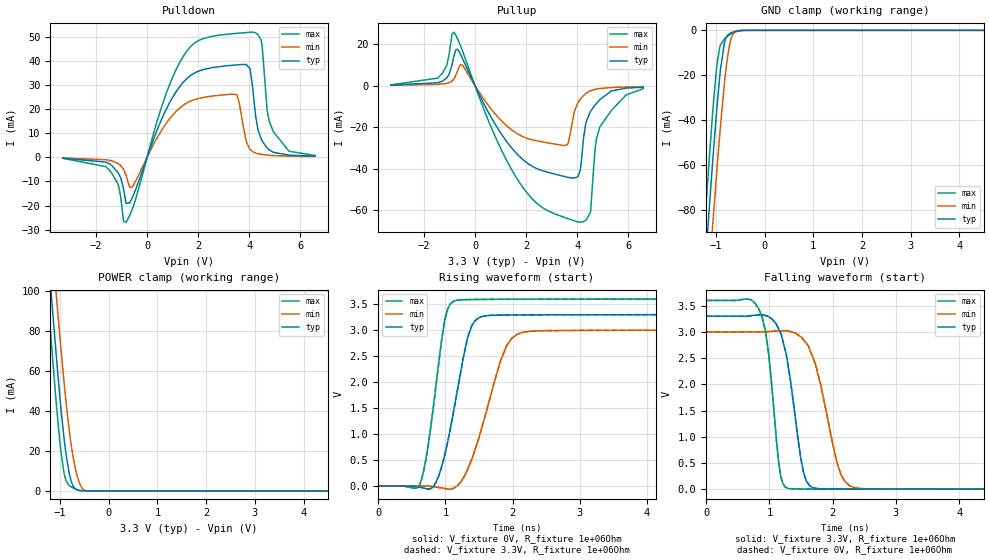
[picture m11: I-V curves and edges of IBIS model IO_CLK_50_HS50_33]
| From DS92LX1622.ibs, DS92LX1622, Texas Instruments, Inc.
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|   IO_CLK_50_HS50 3.3V CLK model
[Model]   IO_CLK_50_HS50_33
Model_type   I/O
Polarity   Non-Inverting
Enable   Active-Low
Vinl = 0.8
Vinh = 2
Vmeas = 1.65
Vref = 3.3
Cref = 1pF
Rref = 1000000
|   typ   min   max
|   (nom)   (fast)   (slow)
C_comp   0.766pF   0.766pF   1.11pF
[Voltage Range]   3.3   3   3.6
[Temperature Range]   25   105   -40
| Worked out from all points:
|   slope of the pulldown table from 0 to 0.495 V, typ, clamps not added: 35.6 ohm
|   slope of the pullup table from 0 to 0.495 V, typ, clamps not added: 40.7 ohm
|   GND clamp passes 1 mA (typ) near -0.67 V on its own axis
|   POWER clamp passes 1 mA (typ) near -0.68 V on its own axis
|   falling waveform, V_fixture 3.3V, R_fixture 1e+06Ohm: 20-80 % time 235ps typ, 327ps min, 176ps max; typ from 3.3 V to 0 V
|   rising waveform, V_fixture 0V, R_fixture 1e+06Ohm: 20-80 % time 294ps typ, 401ps min, 216ps max; typ from 0 V to 3.3 V
|   rising waveform, V_fixture 3.3V, R_fixture 1e+06Ohm: 20-80 % time 294ps typ, 401ps min, 216ps max; typ from 0 V to 3.3 V
|   falling waveform, V_fixture 0V, R_fixture 1e+06Ohm: 20-80 % time 235ps typ, 327ps min, 176ps max; typ from 3.3 V to 0 V
[Pulldown]
|   Voltage   I(typ)   I(min)   I(max)
-3.3V     -398.4uA   -308.3uA   -441uA
-1.607V   -2.004mA   -1.037mA   -3.904mA
-1.142V   -6.345mA   -2.536mA   -11.05mA
-825mV    -19.03mA   -7.469mA   -26.88mA
-597.3mV  -17.1mA    -12.5mA    -21.91mA
1.472V    31.7mA     21.95mA    42.69mA
3.472V    38.2mA     26.05mA    51.26mA
4.125V    29.83mA    2.412mA    51.83mA
4.471V    7.548mA    1.199mA    48.51mA
4.699V    3.892mA    904.3uA    19.71mA
4.947V    2.046mA    714.9uA    10.67mA
6.59V     463.1uA    300.8uA    707.4uA
[GND Clamp]
|   Voltage   I(typ)   I(min)   I(max)
-3.3V     -796.6mA   -801.1mA   -797.6mA
-1.231V   -109mA     -136.6mA   -87.53mA
-1.201V   -99.76mA   -127.6mA   -78.02mA
-1.122V   -75.44mA   -103.8mA   -53.38mA
-1.073V   -60.7mA    -89.17mA   -38.86mA
-983.4mV  -35.83mA   -63.72mA   -16.72mA
-904.2mV  -17.3mA    -42.57mA   -6.459mA
-815.1mV  -4.796mA   -21.95mA   -3.664mA
-735.9mV  -1.721mA   -8.675mA   -2.309mA
-676.5mV  -1.02mA    -3.094mA   -1.5mA
-409.2mV  -14.47uA   -12.9uA    -29.14uA
6.59V     0A         0A         0A
[Pullup]
|   Voltage   I(typ)   I(min)   I(max)
-3.3V     325uA      225.8uA    411.8uA
-1.468V   1.438mA    671.4uA    3.669mA
-825mV    14.44mA    3.308mA    25.83mA
-508.2mV  13.56mA    10.06mA    17.31mA
1.739V    -34mA      -23.65mA   -46.49mA
3.61V     -43.98mA   -28.38mA   -63.84mA
4.125V    -40.45mA   -6.45mA    -65.67mA
4.333V    -18.6mA    -3.802mA   -64.75mA
4.521V    -12.44mA   -2.444mA   -60.89mA
4.709V    -9.242mA   -1.732mA   -29.88mA
4.897V    -6.655mA   -1.329mA   -19.7mA
6.59V     -713uA     -421.4uA   -1.393mA
[POWER Clamp]
|   Voltage   I(typ)   I(min)   I(max)
-3.3V     802.5mA    808.9mA    802mA
-1.31V    139.8mA    168.7mA    117.3mA
-1.231V   114.8mA    144.4mA    91.52mA
-1.211V   108.6mA    138.4mA    85.16mA
-1.132V   84.2mA     114.6mA    60.34mA
-1.082V   69.45mA    100mA      45.61mA
-924mV    27.79mA    56.17mA    9.883mA
-795.3mV  7.174mA    27.45mA    2.45mA
-656.7mV  613.2uA    8.486mA    694.4uA
-547.8mV  99.32uA    1.452mA    115.9uA
-409.2mV  3.688uA    30.95uA    3.022uA
6.59V     0A         0A         0A
[Ramp]
R_load = 1e+06
|   typ   min   max
dV/dt_r   1.97993/2.93867e-10   1.7999/4.01273e-10   2.15993/2.1602e-10
dV/dt_f   1.97994/2.34991e-10   1.79991/3.26556e-10   2.15994/1.75814e-10
[Falling Waveform]
V_fixture = 3.3V
V_fixture_min = 3V
V_fixture_max = 3.6V
R_fixture = 1e+06Ohm
C_fixture = 0F
|   Time   V(typ)   V(min)   V(max)
0s        3.3V       3V         3.6V
880.1ps   3.324V     3.001V     3.305V
989.6ps   3.289V     3.008V     2.567V
1.149ns   3.052V     3.021V     486.8mV
1.289ns   2.404V     3.018V     17.7mV
1.583ns   159.4mV    2.783V     2.849mV
1.728ns   16.75mV    2.389V     2.07mV
2.13ns    2.744mV    283.3mV    1.188mV
2.345ns   1.824mV    28.61mV    995.3uV
10.05ns   105.1uV    134.9uV    93.78uV
[Rising Waveform]
V_fixture = 0V
V_fixture_min = 0V
V_fixture_max = 0V
R_fixture = 1e+06Ohm
C_fixture = 0F
|   Time   V(typ)   V(min)   V(max)
0s        187.7nV    2.409uV    5.075uV
621ps     -25.15mV   268.7uV    38.18mV
828.7ps   3.004mV    -16.09mV   1.599V
989.6ps   594.6mV    -49.13mV   3.191V
1.149ns   1.629V     -23.79mV   3.57V
1.329ns   2.845V     309mV      3.589V
1.436ns   3.173V     675.1mV    3.592V
1.816ns   3.291V     2.39V      3.595V
2.13ns    3.294V     2.951V     3.597V
10.05ns   3.3V       3V         3.6V
[Rising Waveform]
V_fixture = 3.3V
V_fixture_min = 3V
V_fixture_max = 3.6V
R_fixture = 1e+06Ohm
C_fixture = 0F
|   Time   V(typ)   V(min)   V(max)
0s        105.6uV    135.7uV    92.26uV
621ps     -25.03mV   402.1uV    38.52mV
828.7ps   3.49mV     -15.95mV   1.6V
989.6ps   595.5mV    -48.87mV   3.192V
1.149ns   1.63V      -23.19mV   3.57V
1.329ns   2.846V     310mV      3.589V
1.436ns   3.174V     676.3mV    3.592V
1.816ns   3.291V     2.391V     3.595V
2.13ns    3.294V     2.951V     3.597V
10.05ns   3.3V       3V         3.6V
[Falling Waveform]
|Gnd
V_fixture = 0V
V_fixture_min = 0V
V_fixture_max = 0V
R_fixture = 1e+06Ohm
C_fixture = 0F
|   Time   V(typ)   V(min)   V(max)
0s        3.3V       3V         3.6V
880.1ps   3.324V     3V         3.305V
989.6ps   3.289V     3.008V     2.567V
1.149ns   3.052V     3.02V      486.3mV
1.289ns   2.404V     3.018V     17.56mV
1.583ns   159mV      2.783V     2.743mV
1.728ns   16.57mV    2.388V     1.969mV
2.13ns    2.609mV    282.7mV    1.095mV
2.345ns   1.698mV    28.33mV    903.1uV
10.05ns   -346.5nV   1.621uV    6.598uV
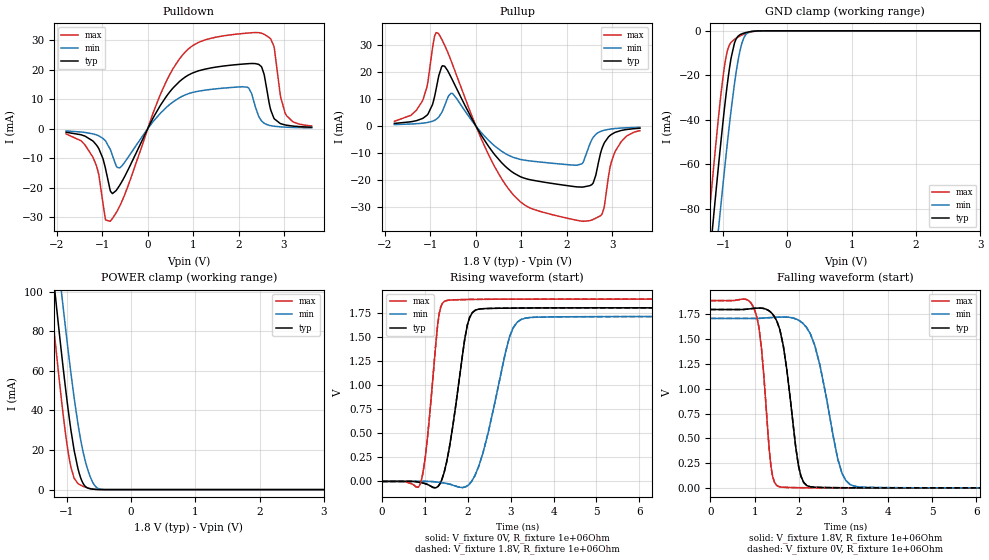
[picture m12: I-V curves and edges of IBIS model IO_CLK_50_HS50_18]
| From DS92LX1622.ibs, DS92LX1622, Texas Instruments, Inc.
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|   IO_CLK_50_HS50 1.8V CLK model
[Model]   IO_CLK_50_HS50_18
Model_type   I/O
Polarity   Non-Inverting
Enable   Active-Low
Vinl = 0.63
Vinh = 1.17
Vmeas = 0.9
Vref = 1.8
Cref = 1pF
Rref = 1000000
|   typ   min   max
|   (nom)   (fast)   (slow)
C_comp   1.11pF   1.11pF   1.11pF
[Voltage Range]   1.8   1.71   1.89
[Temperature Range]   25   105   -40
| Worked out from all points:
|   slope of the pulldown table from 0 to 0.27 V, typ, clamps not added: 35.1 ohm
|   slope of the pullup table from 0 to 0.27 V, typ, clamps not added: 37 ohm
|   GND clamp passes 1 mA (typ) near -0.67 V on its own axis
|   POWER clamp passes 1 mA (typ) near -0.68 V on its own axis
|   falling waveform, V_fixture 1.8V, R_fixture 1e+06Ohm: 20-80 % time 300ps typ, 455ps min, 205ps max; typ from 1.8 V to 0 V
|   rising waveform, V_fixture 0V, R_fixture 1e+06Ohm: 20-80 % time 343ps typ, 516ps min, 231ps max; typ from 0 V to 1.8 V
|   rising waveform, V_fixture 1.8V, R_fixture 1e+06Ohm: 20-80 % time 343ps typ, 516ps min, 231ps max; typ from 0 V to 1.8 V
|   falling waveform, V_fixture 0V, R_fixture 1e+06Ohm: 20-80 % time 300ps typ, 455ps min, 205ps max; typ from 1.8 V to 0 V
[Pulldown]
|   Voltage   I(typ)   I(min)   I(max)
-1.795V   -1.157mA   -724.4uA   -1.742mA
-1.211V   -4.061mA   -1.684mA   -9.46mA
-924mV    -13.77mA   -4.162mA   -30.91mA
-825mV    -20.83mA   -6.906mA   -31.33mA
-607.2mV  -18.91mA   -13.13mA   -25.92mA
699.6mV   16.03mA    10.54mA    23.7mA
2.195V    22.06mA    14.1mA     32.44mA
2.363V    22.11mA    7.84mA     32.62mA
2.511V    20.86mA    2.611mA    32.37mA
2.788V    3.369mA    866.9uA    27.24mA
3.026V    1.312mA    577.4uA    5.296mA
3.61V     564uA      335.2uA    995.5uA
[GND Clamp]
|   Voltage   I(typ)   I(min)   I(max)
-1.795V   -292.4mA   -313.9mA   -276.9mA
-1.31V    -134.1mA   -161mA     -113.3mA
-1.201V   -99.76mA   -127.6mA   -78.02mA
-1.171V   -90.55mA   -118.6mA   -68.64mA
-1.142V   -81.44mA   -109.7mA   -59.42mA
-1.063V   -57.82mA   -86.28mA   -36.08mA
-953.7mV  -28.32mA   -55.58mA   -11.54mA
-874.5mV  -11.92mA   -35.21mA   -5.103mA
-805.2mV  -4.099mA   -19.97mA   -3.476mA
-696.3mV  -1.21mA    -4.515mA   -1.749mA
-468.6mV  -56.35uA   -42.02uA   -115.6uA
6.59V     0A         0A         0A
[Pullup]
|   Voltage   I(typ)   I(min)   I(max)
-1.795V   961.9uA    530.7uA    1.732mA
-1.181V   2.739mA    1.035mA    9.145mA
-914.1mV  10.54mA    2.066mA    32.84mA
-825mV    17.95mA    3.193mA    34.2mA
-518.1mV  17.06mA    12.01mA    22.9mA
699.6mV   -15.69mA   -10.65mA   -22.82mA
2.363V    -22.53mA   -13.37mA   -35.21mA
2.581V    -21.1mA    -4.195mA   -34.52mA
2.779V    -8.126mA   -1.78mA    -32.45mA
2.917V    -4.04mA    -1.236mA   -18.71mA
3.194V    -1.656mA   -759.2uA   -5.867mA
3.61V     -845.5uA   -486.4uA   -1.761mA
[POWER Clamp]
|   Voltage   I(typ)   I(min)   I(max)
-1.795V   298.2mA    321.6mA    281.1mA
-1.261V   124.1mA    153.5mA    101.1mA
-1.221V   111.7mA    141.4mA    88.33mA
-1.181V   99.34mA    129.4mA    75.72mA
-1.073V   66.56mA    97.12mA    42.78mA
-973.5mV  39.44mA    69.22mA    18.22mA
-884.4mV  19.85mA    46.39mA    5.732mA
-775.5mV  5.325mA    23.95mA    2.121mA
-656.7mV  613.2uA    8.486mA    694.4uA
-547.8mV  99.32uA    1.452mA    115.9uA
-409.2mV  3.688uA    30.94uA    3.021uA
6.59V     0A         0A         0A
[Ramp]
R_load = 1e+06
|   typ   min   max
dV/dt_r   1.07996/3.43402e-10   1.02595/5.15866e-10   1.13397/2.31406e-10
dV/dt_f   1.07996/2.99937e-10   1.02595/4.5521e-10   1.13397/2.04775e-10
[Falling Waveform]
V_fixture = 1.8V
V_fixture_min = 1.71V
V_fixture_max = 1.89V
R_fixture = 1e+06Ohm
C_fixture = 0F
|   Time   V(typ)   V(min)   V(max)
0s        1.8V       1.71V      1.89V
1.009ns   1.812V     1.71V      1.784V
1.154ns   1.813V     1.712V     1.411V
1.369ns   1.77V      1.719V     213.4mV
1.538ns   1.636V     1.722V     14.21mV
1.989ns   220.8mV    1.692V     1.825mV
2.177ns   22.92mV    1.613V     1.185mV
2.874ns   1.727mV    290.7mV    429.7uV
3.149ns   1.144mV    34.81mV    326.8uV
10.05ns   56.86uV    85.65uV    41.69uV
[Rising Waveform]
V_fixture = 0V
V_fixture_min = 0V
V_fixture_max = 0V
R_fixture = 1e+06Ohm
C_fixture = 0F
|   Time   V(typ)   V(min)   V(max)
0s        779.8nV    5.958uV    1.186uV
904.8ps   -12.05mV   381.4uV    -6.906mV
1.052ns   -30.44mV   128uV      421.2mV
1.329ns   -37.28mV   -9.456mV   1.733V
1.493ns   176.3mV    -20.51mV   1.874V
1.989ns   1.622V     -44.92mV   1.886V
2.177ns   1.776V     72.8mV     1.887V
2.969ns   1.797V     1.495V     1.889V
3.248ns   1.798V     1.68V      1.89V
10.05ns   1.8V       1.71V      1.89V
[Rising Waveform]
V_fixture = 1.8V
V_fixture_min = 1.71V
V_fixture_max = 1.89V
R_fixture = 1e+06Ohm
C_fixture = 0F
|   Time   V(typ)   V(min)   V(max)
0s        56.85uV    86.11uV    41.52uV
904.8ps   -11.99mV   461uV      -6.601mV
1.052ns   -30.34mV   207.6uV    421.7mV
1.329ns   -36.84mV   -9.365mV   1.733V
1.493ns   176.9mV    -20.39mV   1.874V
1.989ns   1.623V     -44.31mV   1.886V
2.177ns   1.776V     73.6mV     1.887V
2.969ns   1.797V     1.495V     1.89V
3.248ns   1.798V     1.68V      1.89V
10.05ns   1.8V       1.71V      1.89V
[Falling Waveform]
|Gnd
V_fixture = 0V
V_fixture_min = 0V
V_fixture_max = 0V
R_fixture = 1e+06Ohm
C_fixture = 0F
|   Time   V(typ)   V(min)   V(max)
0s        1.8V       1.71V      1.89V
1.009ns   1.812V     1.71V      1.784V
1.154ns   1.813V     1.712V     1.411V
1.369ns   1.77V      1.719V     213.2mV
1.538ns   1.635V     1.722V     14.14mV
1.989ns   220.5mV    1.692V     1.776mV
2.177ns   22.8mV     1.613V     1.139mV
2.874ns   1.658mV    290.2mV    387.3uV
3.149ns   1.079mV    34.6mV     284.9uV
10.05ns   791.9nV    5.504uV    1.358uV
